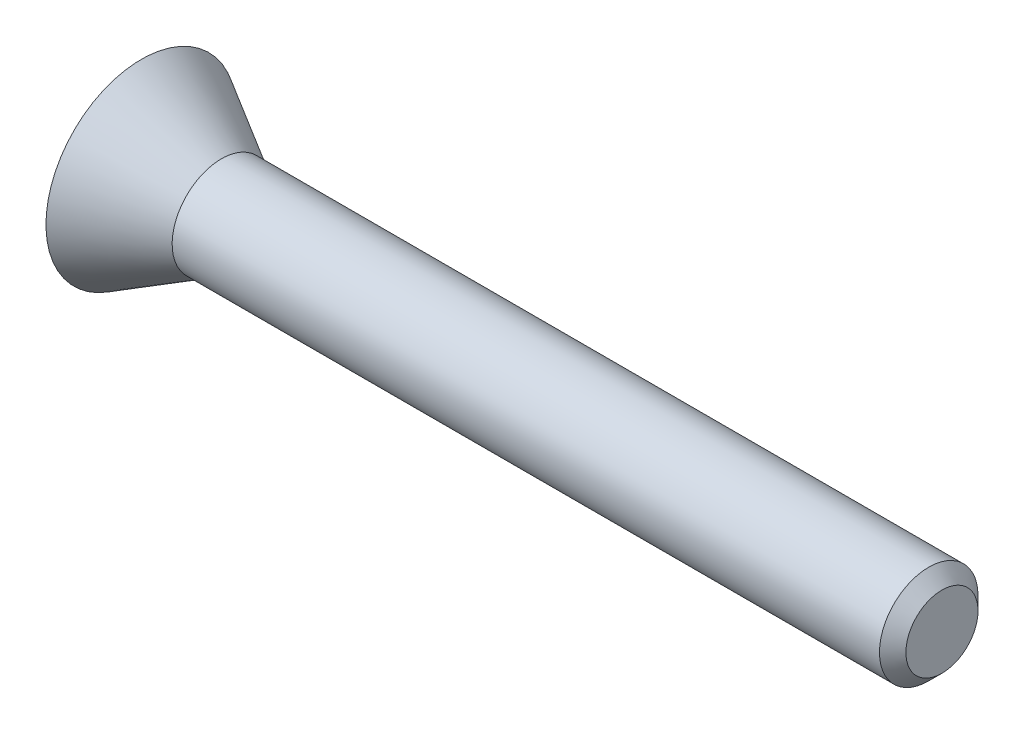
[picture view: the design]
ISO-10303-21;
HEADER;
FILE_DESCRIPTION(('STEP AP214'),'2;1');
FILE_NAME('part.step','',(''),(''),'','','');
FILE_SCHEMA(('AUTOMOTIVE_DESIGN { 1 0 10303 214 1 1 1 1 }'));
ENDSEC;
DATA;
#1=APPLICATION_CONTEXT('core data for automotive mechanical design processes');
#2=APPLICATION_PROTOCOL_DEFINITION('international standard','automotive_design',2000,#1);
#3=PRODUCT_CONTEXT('',#1,'mechanical');
#4=PRODUCT('Part','Part','',(#3));
#5=PRODUCT_RELATED_PRODUCT_CATEGORY('part','',(#4));
#6=PRODUCT_DEFINITION_FORMATION('','',#4);
#7=PRODUCT_DEFINITION_CONTEXT('part definition',#1,'design');
#8=PRODUCT_DEFINITION('design','',#6,#7);
#9=PRODUCT_DEFINITION_SHAPE('','',#8);
#10=(LENGTH_UNIT() NAMED_UNIT(*) SI_UNIT(.MILLI.,.METRE.));
#11=(NAMED_UNIT(*) PLANE_ANGLE_UNIT() SI_UNIT($,.RADIAN.));
#12=(NAMED_UNIT(*) SI_UNIT($,.STERADIAN.) SOLID_ANGLE_UNIT());
#13=UNCERTAINTY_MEASURE_WITH_UNIT(LENGTH_MEASURE(1.E-05),#10,'distance_accuracy_value','');
#14=(GEOMETRIC_REPRESENTATION_CONTEXT(3) GLOBAL_UNCERTAINTY_ASSIGNED_CONTEXT((#13)) GLOBAL_UNIT_ASSIGNED_CONTEXT((#10,
#11,#12)) REPRESENTATION_CONTEXT('',''));
#15=CARTESIAN_POINT('',(0.,0.,0.));
#16=DIRECTION('',(0.,0.,1.));
#17=DIRECTION('',(1.,0.,0.));
#18=AXIS2_PLACEMENT_3D('',#15,#16,#17);
#19=CARTESIAN_POINT('',(-6.5,0.,0.));
#20=DIRECTION('',(1.,0.,0.));
#21=DIRECTION('',(0.,0.,-1.));
#22=AXIS2_PLACEMENT_3D('',#19,#20,#21);
#23=PLANE('',#22);
#24=DIRECTION('',(0.,-1.,0.));
#25=VECTOR('',#24,1.);
#26=CARTESIAN_POINT('',(-6.5,0.45,-0.99468363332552));
#27=LINE('',#26,#25);
#28=CARTESIAN_POINT('',(-6.5,0.45,-0.99468363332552));
#29=VERTEX_POINT('',#28);
#30=CARTESIAN_POINT('',(-6.5,0.299512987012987,-0.99468363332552));
#31=VERTEX_POINT('',#30);
#32=EDGE_CURVE('E298',#29,#31,#27,.T.);
#33=ORIENTED_EDGE('',*,*,#32,.F.);
#34=DIRECTION('',(0.,0.,-1.));
#35=VECTOR('',#34,1.);
#36=CARTESIAN_POINT('',(-6.5,0.45,-0.311891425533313));
#37=LINE('',#36,#35);
#38=CARTESIAN_POINT('',(-6.5,0.45,-0.311891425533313));
#39=VERTEX_POINT('',#38);
#40=EDGE_CURVE('E54',#39,#29,#37,.T.);
#41=ORIENTED_EDGE('',*,*,#40,.F.);
#42=DIRECTION('',(0.,1.,0.));
#43=VECTOR('',#42,1.);
#44=CARTESIAN_POINT('',(-6.5,0.0448051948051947,-0.311891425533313));
#45=LINE('',#44,#43);
#46=CARTESIAN_POINT('',(-6.5,0.0448051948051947,-0.311891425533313));
#47=VERTEX_POINT('',#46);
#48=EDGE_CURVE('E275',#47,#39,#45,.T.);
#49=ORIENTED_EDGE('',*,*,#48,.F.);
#50=DIRECTION('',(0.,0.,1.));
#51=VECTOR('',#50,1.);
#52=CARTESIAN_POINT('',(-6.5,0.0448051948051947,-0.537134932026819));
#53=LINE('',#52,#51);
#54=CARTESIAN_POINT('',(-6.5,0.0448051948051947,-0.537134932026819));
#55=VERTEX_POINT('',#54);
#56=EDGE_CURVE('E278',#55,#47,#53,.T.);
#57=ORIENTED_EDGE('',*,*,#56,.F.);
#58=DIRECTION('',(0.,-1.,0.));
#59=VECTOR('',#58,1.);
#60=CARTESIAN_POINT('',(-6.5,0.231818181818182,-0.537134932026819));
#61=LINE('',#60,#59);
#62=CARTESIAN_POINT('',(-6.5,0.231818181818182,-0.537134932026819));
#63=VERTEX_POINT('',#62);
#64=EDGE_CURVE('E312',#63,#55,#61,.T.);
#65=ORIENTED_EDGE('',*,*,#64,.F.);
#66=DIRECTION('',(0.,0.,1.));
#67=VECTOR('',#66,1.);
#68=CARTESIAN_POINT('',(-6.5,0.231818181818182,-0.742410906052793));
#69=LINE('',#68,#67);
#70=CARTESIAN_POINT('',(-6.5,0.231818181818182,-0.742410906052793));
#71=VERTEX_POINT('',#70);
#72=EDGE_CURVE('E309',#71,#63,#69,.T.);
#73=ORIENTED_EDGE('',*,*,#72,.F.);
#74=DIRECTION('',(0.,0.966781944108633,-0.255602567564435));
#75=VECTOR('',#74,1.);
#76=CARTESIAN_POINT('',(-6.5,-0.75,-0.482832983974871));
#77=LINE('',#76,#75);
#78=CARTESIAN_POINT('',(-6.5,-0.75,-0.482832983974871));
#79=VERTEX_POINT('',#78);
#80=EDGE_CURVE('E306',#79,#71,#77,.T.);
#81=ORIENTED_EDGE('',*,*,#80,.F.);
#82=DIRECTION('',(0.,0.,1.));
#83=VECTOR('',#82,1.);
#84=CARTESIAN_POINT('',(-6.5,-0.75,-0.726826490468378));
#85=LINE('',#84,#83);
#86=CARTESIAN_POINT('',(-6.5,-0.75,-0.726826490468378));
#87=VERTEX_POINT('',#86);
#88=EDGE_CURVE('E303',#87,#79,#85,.T.);
#89=ORIENTED_EDGE('',*,*,#88,.F.);
#90=DIRECTION('',(0.,-0.968940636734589,0.247293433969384));
#91=VECTOR('',#90,1.);
#92=CARTESIAN_POINT('',(-6.5,0.299512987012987,-0.99468363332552));
#93=LINE('',#92,#91);
#94=EDGE_CURVE('E300',#31,#87,#93,.T.);
#95=ORIENTED_EDGE('',*,*,#94,.F.);
#96=EDGE_LOOP('',(#33,#41,#49,#57,#65,#73,#81,#89,#95));
#97=FACE_BOUND('',#96,.T.);
#98=DIRECTION('',(0.,1.,0.));
#99=VECTOR('',#98,1.);
#100=CARTESIAN_POINT('',(-6.5,-0.75,1.02208584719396));
#101=LINE('',#100,#99);
#102=CARTESIAN_POINT('',(-6.5,-0.75,1.02208584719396));
#103=VERTEX_POINT('',#102);
#104=CARTESIAN_POINT('',(-6.5,-0.545941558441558,1.02208584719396));
#105=VERTEX_POINT('',#104);
#106=EDGE_CURVE('E427',#103,#105,#101,.T.);
#107=ORIENTED_EDGE('',*,*,#106,.F.);
#108=DIRECTION('',(0.,0.,1.));
#109=VECTOR('',#108,1.);
#110=CARTESIAN_POINT('',(-6.5,-0.75,0.315430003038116));
#111=LINE('',#110,#109);
#112=CARTESIAN_POINT('',(-6.5,-0.75,0.315430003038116));
#113=VERTEX_POINT('',#112);
#114=EDGE_CURVE('E62',#113,#103,#111,.T.);
#115=ORIENTED_EDGE('',*,*,#114,.F.);
#116=DIRECTION('',(0.,-1.,0.));
#117=VECTOR('',#116,1.);
#118=CARTESIAN_POINT('',(-6.5,-0.531818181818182,0.315430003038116));
#119=LINE('',#118,#117);
#120=CARTESIAN_POINT('',(-6.5,-0.531818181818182,0.315430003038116));
#121=VERTEX_POINT('',#120);
#122=EDGE_CURVE('E336',#121,#113,#119,.T.);
#123=ORIENTED_EDGE('',*,*,#122,.F.);
#124=DIRECTION('',(0.,0.,-1.));
#125=VECTOR('',#124,1.);
#126=CARTESIAN_POINT('',(-6.5,-0.531818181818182,0.723790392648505));
#127=LINE('',#126,#125);
#128=CARTESIAN_POINT('',(-6.5,-0.531818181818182,0.723790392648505));
#129=VERTEX_POINT('',#128);
#130=EDGE_CURVE('E535',#129,#121,#127,.T.);
#131=ORIENTED_EDGE('',*,*,#130,.F.);
#132=DIRECTION('',(0.,-0.786034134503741,0.618183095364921));
#133=VECTOR('',#132,1.);
#134=CARTESIAN_POINT('',(-6.5,-0.157792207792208,0.429634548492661));
#135=LINE('',#134,#133);
#136=CARTESIAN_POINT('',(-6.5,-0.157792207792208,0.429634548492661));
#137=VERTEX_POINT('',#136);
#138=EDGE_CURVE('E538',#137,#129,#135,.T.);
#139=ORIENTED_EDGE('',*,*,#138,.F.);
#140=CARTESIAN_POINT('',(-6.5,0.150974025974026,0.322004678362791));
#141=CARTESIAN_POINT('',(-6.5,0.137320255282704,0.322315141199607));
#142=CARTESIAN_POINT('',(-6.5,0.10998858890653,0.322936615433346));
#143=CARTESIAN_POINT('',(-6.5,0.069082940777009,0.328546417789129));
#144=CARTESIAN_POINT('',(-6.5,0.0283861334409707,0.337586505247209));
#145=CARTESIAN_POINT('',(-6.5,-0.0119052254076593,0.350001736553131));
#146=CARTESIAN_POINT('',(-6.5,-0.0510932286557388,0.365424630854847));
#147=CARTESIAN_POINT('',(-6.5,-0.0886411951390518,0.383935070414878));
#148=CARTESIAN_POINT('',(-6.5,-0.124565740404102,0.404826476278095));
#149=CARTESIAN_POINT('',(-6.5,-0.146737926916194,0.421381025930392));
#150=CARTESIAN_POINT('',(-6.5,-0.157792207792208,0.429634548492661));
#151=B_SPLINE_CURVE_WITH_KNOTS('',3,(#140,#141,#142,#143,#144,#145,#146,#147,#148,#149,#150),
.UNSPECIFIED.,.F.,.F.,(4,1,1,1,1,1,1,1,4),(0.,0.123046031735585,0.246309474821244,
0.371480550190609,0.498560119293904,0.626024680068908,0.750715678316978,0.875715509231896,1.),.UNSPECIFIED.);
#152=CARTESIAN_POINT('',(-6.5,0.150974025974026,0.322004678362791));
#153=VERTEX_POINT('',#152);
#154=EDGE_CURVE('E541',#153,#137,#151,.T.);
#155=ORIENTED_EDGE('',*,*,#154,.F.);
#156=DIRECTION('',(0.,-1.,0.));
#157=VECTOR('',#156,1.);
#158=CARTESIAN_POINT('',(-6.5,0.151948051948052,0.322004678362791));
#159=LINE('',#158,#157);
#160=CARTESIAN_POINT('',(-6.5,0.151948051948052,0.322004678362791));
#161=VERTEX_POINT('',#160);
#162=EDGE_CURVE('E546',#161,#153,#159,.T.);
#163=ORIENTED_EDGE('',*,*,#162,.F.);
#164=CARTESIAN_POINT('',(-6.5,0.465584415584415,0.675332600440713));
#165=CARTESIAN_POINT('',(-6.5,0.465390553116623,0.661685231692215));
#166=CARTESIAN_POINT('',(-6.5,0.465013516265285,0.635142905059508));
#167=CARTESIAN_POINT('',(-6.5,0.460943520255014,0.596501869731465));
#168=CARTESIAN_POINT('',(-6.5,0.454800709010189,0.560144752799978));
#169=CARTESIAN_POINT('',(-6.5,0.445814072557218,0.526130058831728));
#170=CARTESIAN_POINT('',(-6.5,0.434091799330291,0.494594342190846));
#171=CARTESIAN_POINT('',(-6.5,0.419957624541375,0.465443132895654));
#172=CARTESIAN_POINT('',(-6.5,0.403291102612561,0.43861549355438));
#173=CARTESIAN_POINT('',(-6.5,0.38405660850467,0.414316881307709));
#174=CARTESIAN_POINT('',(-6.5,0.362603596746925,0.392454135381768));
#175=CARTESIAN_POINT('',(-6.5,0.338714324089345,0.373636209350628));
#176=CARTESIAN_POINT('',(-6.5,0.312871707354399,0.35734617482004));
#177=CARTESIAN_POINT('',(-6.5,0.2845745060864,0.344612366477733));
#178=CARTESIAN_POINT('',(-6.5,0.254488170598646,0.334128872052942));
#179=CARTESIAN_POINT('',(-6.5,0.222073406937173,0.327340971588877));
#180=CARTESIAN_POINT('',(-6.5,0.187711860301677,0.322766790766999));
#181=CARTESIAN_POINT('',(-6.5,0.164058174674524,0.322262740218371));
#182=CARTESIAN_POINT('',(-6.5,0.151948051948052,0.322004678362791));
#183=B_SPLINE_CURVE_WITH_KNOTS('',3,(#164,#165,#166,#167,#168,#169,#170,#171,#172,#173,#174,
#175,#176,#177,#178,#179,#180,#181,#182),.UNSPECIFIED.,.F.,.F.,(4,1,1,1,1,1,1,1,1,1,1,1,1,1,1,1,
4),(0.,0.0762312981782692,0.148259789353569,0.216860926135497,0.28210063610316,
0.344528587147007,0.404571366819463,0.462840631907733,0.520642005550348,0.577409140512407,
0.633580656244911,0.690215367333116,0.747647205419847,0.806597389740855,0.867894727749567,
0.932365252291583,1.),.UNSPECIFIED.);
#184=CARTESIAN_POINT('',(-6.5,0.465584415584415,0.675332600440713));
#185=VERTEX_POINT('',#184);
#186=EDGE_CURVE('E552',#185,#161,#183,.T.);
#187=ORIENTED_EDGE('',*,*,#186,.F.);
#188=CARTESIAN_POINT('',(-6.5,0.105438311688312,1.03693974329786));
#189=CARTESIAN_POINT('',(-6.5,0.11934799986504,1.03580067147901));
#190=CARTESIAN_POINT('',(-6.5,0.146499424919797,1.03357722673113));
#191=CARTESIAN_POINT('',(-6.5,0.185775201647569,1.02628780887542));
#192=CARTESIAN_POINT('',(-6.5,0.22277029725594,1.0168665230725));
#193=CARTESIAN_POINT('',(-6.5,0.257477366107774,1.00488137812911));
#194=CARTESIAN_POINT('',(-6.5,0.289494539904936,0.989480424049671));
#195=CARTESIAN_POINT('',(-6.5,0.3194911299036,0.972176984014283));
#196=CARTESIAN_POINT('',(-6.5,0.346539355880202,0.95136528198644));
#197=CARTESIAN_POINT('',(-6.5,0.371544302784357,0.928583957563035));
#198=CARTESIAN_POINT('',(-6.5,0.393568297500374,0.903209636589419));
#199=CARTESIAN_POINT('',(-6.5,0.412996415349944,0.876153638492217));
#200=CARTESIAN_POINT('',(-6.5,0.429163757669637,0.847006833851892));
#201=CARTESIAN_POINT('',(-6.5,0.442575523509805,0.81621233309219));
#202=CARTESIAN_POINT('',(-6.5,0.452754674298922,0.78342871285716));
#203=CARTESIAN_POINT('',(-6.5,0.460379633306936,0.749084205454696));
#204=CARTESIAN_POINT('',(-6.5,0.464776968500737,0.71278460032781));
#205=CARTESIAN_POINT('',(-6.5,0.465311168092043,0.688006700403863));
#206=CARTESIAN_POINT('',(-6.5,0.465584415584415,0.675332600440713));
#207=B_SPLINE_CURVE_WITH_KNOTS('',3,(#188,#189,#190,#191,#192,#193,#194,#195,#196,#197,#198,
#199,#200,#201,#202,#203,#204,#205,#206),.UNSPECIFIED.,.F.,.F.,(4,1,1,1,1,1,1,1,1,1,1,1,1,1,1,1,
4),(0.,0.0733268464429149,0.14313249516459,0.209679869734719,0.273918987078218,0.33576228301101,
0.396210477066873,0.45560885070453,0.514796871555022,0.573764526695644,0.631900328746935,
0.689592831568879,0.748648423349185,0.808163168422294,0.86976604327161,0.933384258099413,1.),.UNSPECIFIED.);
#208=CARTESIAN_POINT('',(-6.5,0.105438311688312,1.03693974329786));
#209=VERTEX_POINT('',#208);
#210=EDGE_CURVE('E557',#209,#185,#207,.T.);
#211=ORIENTED_EDGE('',*,*,#210,.F.);
#212=DIRECTION('',(0.,1.,0.));
#213=VECTOR('',#212,1.);
#214=CARTESIAN_POINT('',(-6.5,0.104707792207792,1.03693974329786));
#215=LINE('',#214,#213);
#216=CARTESIAN_POINT('',(-6.5,0.104707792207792,1.03693974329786));
#217=VERTEX_POINT('',#216);
#218=EDGE_CURVE('E565',#217,#209,#215,.T.);
#219=ORIENTED_EDGE('',*,*,#218,.F.);
#220=DIRECTION('',(0.,0.,1.));
#221=VECTOR('',#220,1.);
#222=CARTESIAN_POINT('',(-6.5,0.104707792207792,0.8060955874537));
#223=LINE('',#222,#221);
#224=CARTESIAN_POINT('',(-6.5,0.104707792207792,0.8060955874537));
#225=VERTEX_POINT('',#224);
#226=EDGE_CURVE('E571',#225,#217,#223,.T.);
#227=ORIENTED_EDGE('',*,*,#226,.F.);
#228=DIRECTION('',(0.,-1.,0.));
#229=VECTOR('',#228,1.);
#230=CARTESIAN_POINT('',(-6.5,0.105438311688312,0.8060955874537));
#231=LINE('',#230,#229);
#232=CARTESIAN_POINT('',(-6.5,0.105438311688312,0.8060955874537));
#233=VERTEX_POINT('',#232);
#234=EDGE_CURVE('E574',#233,#225,#231,.T.);
#235=ORIENTED_EDGE('',*,*,#234,.F.);
#236=CARTESIAN_POINT('',(-6.5,0.247402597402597,0.673628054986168));
#237=CARTESIAN_POINT('',(-6.5,0.247058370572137,0.682449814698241));
#238=CARTESIAN_POINT('',(-6.5,0.246389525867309,0.699590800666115));
#239=CARTESIAN_POINT('',(-6.5,0.238976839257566,0.723856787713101));
#240=CARTESIAN_POINT('',(-6.5,0.227349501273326,0.745722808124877));
#241=CARTESIAN_POINT('',(-6.5,0.210758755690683,0.764573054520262));
#242=CARTESIAN_POINT('',(-6.5,0.189928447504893,0.78018248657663));
#243=CARTESIAN_POINT('',(-6.5,0.165399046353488,0.792851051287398));
#244=CARTESIAN_POINT('',(-6.5,0.136727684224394,0.801455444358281));
#245=CARTESIAN_POINT('',(-6.5,0.116203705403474,0.804499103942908));
#246=CARTESIAN_POINT('',(-6.5,0.105438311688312,0.8060955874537));
#247=B_SPLINE_CURVE_WITH_KNOTS('',3,(#236,#237,#238,#239,#240,#241,#242,#243,#244,#245,#246),
.UNSPECIFIED.,.F.,.F.,(4,1,1,1,1,1,1,1,4),(0.,0.122603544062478,0.238222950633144,
0.350089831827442,0.465559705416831,0.58502806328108,0.711014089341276,0.848418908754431,1.),.UNSPECIFIED.);
#248=CARTESIAN_POINT('',(-6.5,0.247402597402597,0.673628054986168));
#249=VERTEX_POINT('',#248);
#250=EDGE_CURVE('E577',#249,#233,#247,.T.);
#251=ORIENTED_EDGE('',*,*,#250,.F.);
#252=CARTESIAN_POINT('',(-6.5,0.145616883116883,0.553822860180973));
#253=CARTESIAN_POINT('',(-6.5,0.153289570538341,0.554155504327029));
#254=CARTESIAN_POINT('',(-6.5,0.16798921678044,0.55479279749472));
#255=CARTESIAN_POINT('',(-6.5,0.188701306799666,0.560797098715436));
#256=CARTESIAN_POINT('',(-6.5,0.206738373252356,0.570637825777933));
#257=CARTESIAN_POINT('',(-6.5,0.221636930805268,0.584732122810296));
#258=CARTESIAN_POINT('',(-6.5,0.233420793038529,0.602278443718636));
#259=CARTESIAN_POINT('',(-6.5,0.241725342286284,0.623273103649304));
#260=CARTESIAN_POINT('',(-6.5,0.246487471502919,0.647441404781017));
#261=CARTESIAN_POINT('',(-6.5,0.247086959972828,0.664595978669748));
#262=CARTESIAN_POINT('',(-6.5,0.247402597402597,0.673628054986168));
#263=B_SPLINE_CURVE_WITH_KNOTS('',3,(#252,#253,#254,#255,#256,#257,#258,#259,#260,#261,#262),
.UNSPECIFIED.,.F.,.F.,(4,1,1,1,1,1,1,1,4),(0.,0.128749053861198,0.246662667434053,
0.359069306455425,0.47107757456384,0.588039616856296,0.711712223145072,0.848213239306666,1.),.UNSPECIFIED.);
#264=CARTESIAN_POINT('',(-6.5,0.145616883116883,0.553822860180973));
#265=VERTEX_POINT('',#264);
#266=EDGE_CURVE('E582',#265,#249,#263,.T.);
#267=ORIENTED_EDGE('',*,*,#266,.F.);
#268=DIRECTION('',(0.,1.,0.));
#269=VECTOR('',#268,1.);
#270=CARTESIAN_POINT('',(-6.5,0.143912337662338,0.553822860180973));
#271=LINE('',#270,#269);
#272=CARTESIAN_POINT('',(-6.5,0.143912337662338,0.553822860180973));
#273=VERTEX_POINT('',#272);
#274=EDGE_CURVE('E590',#273,#265,#271,.T.);
#275=ORIENTED_EDGE('',*,*,#274,.F.);
#276=CARTESIAN_POINT('',(-6.5,-0.00267857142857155,0.612020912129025));
#277=CARTESIAN_POINT('',(-6.5,0.00942362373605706,0.603432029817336));
#278=CARTESIAN_POINT('',(-6.5,0.0330043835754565,0.586696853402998));
#279=CARTESIAN_POINT('',(-6.5,0.0653877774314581,0.571550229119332));
#280=CARTESIAN_POINT('',(-6.5,0.0907767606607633,0.562114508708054));
#281=CARTESIAN_POINT('',(-6.5,0.109188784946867,0.557617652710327));
#282=CARTESIAN_POINT('',(-6.5,0.126755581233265,0.554409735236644));
#283=CARTESIAN_POINT('',(-6.5,0.138298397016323,0.55401489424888));
#284=CARTESIAN_POINT('',(-6.5,0.143912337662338,0.553822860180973));
#285=B_SPLINE_CURVE_WITH_KNOTS('',3,(#276,#277,#278,#279,#280,#281,#282,#283,#284),
.UNSPECIFIED.,.F.,.F.,(4,1,1,1,1,1,4),(0.,0.27737542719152,0.540457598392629,0.666416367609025,
0.784009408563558,0.894951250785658,1.),.UNSPECIFIED.);
#286=CARTESIAN_POINT('',(-6.5,-0.00267857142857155,0.612020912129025));
#287=VERTEX_POINT('',#286);
#288=EDGE_CURVE('E596',#287,#273,#285,.T.);
#289=ORIENTED_EDGE('',*,*,#288,.F.);
#290=DIRECTION('',(0.,0.798150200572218,-0.602458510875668));
#291=VECTOR('',#290,1.);
#292=CARTESIAN_POINT('',(-6.5,-0.545941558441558,1.02208584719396));
#293=LINE('',#292,#291);
#294=EDGE_CURVE('E601',#105,#287,#293,.T.);
#295=ORIENTED_EDGE('',*,*,#294,.F.);
#296=EDGE_LOOP('',(#107,#115,#123,#131,#139,#155,#163,#187,#211,#219,#227,#235,#251,#267,#275,
#289,#295));
#297=FACE_BOUND('',#296,.T.);
#298=DIRECTION('',(0.,1.,0.));
#299=VECTOR('',#298,1.);
#300=CARTESIAN_POINT('',(-6.5,0.68,0.155));
#301=LINE('',#300,#299);
#302=CARTESIAN_POINT('',(-6.5,-1.025,0.155));
#303=VERTEX_POINT('',#302);
#304=CARTESIAN_POINT('',(-6.5,0.68,0.155));
#305=VERTEX_POINT('',#304);
#306=EDGE_CURVE('E433',#303,#305,#301,.T.);
#307=ORIENTED_EDGE('',*,*,#306,.F.);
#308=CARTESIAN_POINT('',(-6.5,-1.025,0.));
#309=DIRECTION('',(-1.,0.,0.));
#310=DIRECTION('',(0.,0.,1.));
#311=AXIS2_PLACEMENT_3D('',#308,#309,#310);
#312=CIRCLE('',#311,0.155);
#313=CARTESIAN_POINT('',(-6.5,-1.025,-0.155));
#314=VERTEX_POINT('',#313);
#315=EDGE_CURVE('E477',#314,#303,#312,.T.);
#316=ORIENTED_EDGE('',*,*,#315,.F.);
#317=DIRECTION('',(0.,-1.,0.));
#318=VECTOR('',#317,1.);
#319=CARTESIAN_POINT('',(-6.5,0.68,-0.155));
#320=LINE('',#319,#318);
#321=CARTESIAN_POINT('',(-6.5,0.68,-0.155));
#322=VERTEX_POINT('',#321);
#323=EDGE_CURVE('E460',#322,#314,#320,.T.);
#324=ORIENTED_EDGE('',*,*,#323,.F.);
#325=DIRECTION('',(0.,0.,1.));
#326=VECTOR('',#325,1.);
#327=CARTESIAN_POINT('',(-6.5,0.68,-0.37));
#328=LINE('',#327,#326);
#329=CARTESIAN_POINT('',(-6.5,0.68,-0.37));
#330=VERTEX_POINT('',#329);
#331=EDGE_CURVE('E464',#330,#322,#328,.T.);
#332=ORIENTED_EDGE('',*,*,#331,.F.);
#333=DIRECTION('',(0.,-0.858712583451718,-0.512457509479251));
#334=VECTOR('',#333,1.);
#335=CARTESIAN_POINT('',(-6.5,1.3,0.));
#336=LINE('',#335,#334);
#337=CARTESIAN_POINT('',(-6.5,1.3,0.));
#338=VERTEX_POINT('',#337);
#339=EDGE_CURVE('E467',#338,#330,#336,.T.);
#340=ORIENTED_EDGE('',*,*,#339,.F.);
#341=DIRECTION('',(0.,0.858712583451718,-0.512457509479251));
#342=VECTOR('',#341,1.);
#343=CARTESIAN_POINT('',(-6.5,1.3,0.));
#344=LINE('',#343,#342);
#345=CARTESIAN_POINT('',(-6.5,0.68,0.37));
#346=VERTEX_POINT('',#345);
#347=EDGE_CURVE('E470',#346,#338,#344,.T.);
#348=ORIENTED_EDGE('',*,*,#347,.F.);
#349=DIRECTION('',(0.,0.,1.));
#350=VECTOR('',#349,1.);
#351=CARTESIAN_POINT('',(-6.5,0.68,0.37));
#352=LINE('',#351,#350);
#353=EDGE_CURVE('E473',#305,#346,#352,.T.);
#354=ORIENTED_EDGE('',*,*,#353,.F.);
#355=EDGE_LOOP('',(#307,#316,#324,#332,#340,#348,#354));
#356=FACE_BOUND('',#355,.T.);
#357=CARTESIAN_POINT('',(-6.5,0.,0.));
#358=DIRECTION('',(-1.,0.,0.));
#359=DIRECTION('',(0.,-1.,0.));
#360=AXIS2_PLACEMENT_3D('',#357,#358,#359);
#361=CIRCLE('',#360,1.55);
#362=CARTESIAN_POINT('',(-6.5,-1.55000000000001,0.));
#363=VERTEX_POINT('',#362);
#364=EDGE_CURVE('E436',#363,#363,#361,.T.);
#365=ORIENTED_EDGE('',*,*,#364,.T.);
#366=EDGE_LOOP('',(#365));
#367=FACE_BOUND('',#366,.T.);
#368=ADVANCED_FACE('F39',(#97,#297,#356,#367),#23,.F.);
#369=CARTESIAN_POINT('',(-6.5,0.,0.));
#370=DIRECTION('',(-1.,0.,0.));
#371=DIRECTION('',(0.,-1.,0.));
#372=AXIS2_PLACEMENT_3D('',#369,#370,#371);
#373=CONICAL_SURFACE('',#372,1.55,0.523598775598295);
#374=CARTESIAN_POINT('',(-5.20096189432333,0.,0.));
#375=DIRECTION('',(-1.,0.,0.));
#376=DIRECTION('',(0.,-1.,0.));
#377=AXIS2_PLACEMENT_3D('',#374,#375,#376);
#378=CIRCLE('',#377,0.800000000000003);
#379=CARTESIAN_POINT('',(-5.20096189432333,-0.800000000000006,0.));
#380=VERTEX_POINT('',#379);
#381=EDGE_CURVE('E438',#380,#380,#378,.T.);
#382=ORIENTED_EDGE('',*,*,#381,.T.);
#383=EDGE_LOOP('',(#382));
#384=FACE_BOUND('',#383,.T.);
#385=ORIENTED_EDGE('',*,*,#364,.F.);
#386=EDGE_LOOP('',(#385));
#387=FACE_BOUND('',#386,.T.);
#388=ADVANCED_FACE('F410',(#384,#387),#373,.T.);
#389=CARTESIAN_POINT('',(-6.5,0.,0.));
#390=DIRECTION('',(-1.,0.,0.));
#391=DIRECTION('',(0.,-1.,0.));
#392=AXIS2_PLACEMENT_3D('',#389,#390,#391);
#393=CYLINDRICAL_SURFACE('',#392,0.800000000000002);
#394=CARTESIAN_POINT('',(6.2855,0.,0.));
#395=DIRECTION('',(1.,0.,0.));
#396=DIRECTION('',(0.,1.,0.));
#397=AXIS2_PLACEMENT_3D('',#394,#395,#396);
#398=CIRCLE('',#397,0.800000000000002);
#399=CARTESIAN_POINT('',(6.2855,0.800000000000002,0.));
#400=VERTEX_POINT('',#399);
#401=EDGE_CURVE('E47',#400,#400,#398,.F.);
#402=ORIENTED_EDGE('',*,*,#401,.T.);
#403=EDGE_LOOP('',(#402));
#404=FACE_BOUND('',#403,.T.);
#405=ORIENTED_EDGE('',*,*,#381,.F.);
#406=EDGE_LOOP('',(#405));
#407=FACE_BOUND('',#406,.T.);
#408=ADVANCED_FACE('F407',(#404,#407),#393,.T.);
#409=CARTESIAN_POINT('',(6.5,0.,0.));
#410=DIRECTION('',(1.,0.,0.));
#411=DIRECTION('',(0.,0.,-1.));
#412=AXIS2_PLACEMENT_3D('',#409,#410,#411);
#413=PLANE('',#412);
#414=CARTESIAN_POINT('',(6.5,0.,0.));
#415=DIRECTION('',(1.,0.,0.));
#416=DIRECTION('',(0.,0.,-1.));
#417=AXIS2_PLACEMENT_3D('',#414,#415,#416);
#418=CIRCLE('',#417,0.585500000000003);
#419=CARTESIAN_POINT('',(6.5,0.,-0.585500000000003));
#420=VERTEX_POINT('',#419);
#421=EDGE_CURVE('E11',#420,#420,#418,.T.);
#422=ORIENTED_EDGE('',*,*,#421,.T.);
#423=EDGE_LOOP('',(#422));
#424=FACE_BOUND('',#423,.T.);
#425=ADVANCED_FACE('F405',(#424),#413,.T.);
#426=CARTESIAN_POINT('',(-6.1,-1.025,0.));
#427=DIRECTION('',(-1.,0.,0.));
#428=DIRECTION('',(0.,0.,1.));
#429=AXIS2_PLACEMENT_3D('',#426,#427,#428);
#430=CYLINDRICAL_SURFACE('',#429,0.155);
#431=ORIENTED_EDGE('',*,*,#315,.T.);
#432=DIRECTION('',(-1.,0.,0.));
#433=VECTOR('',#432,1.);
#434=CARTESIAN_POINT('',(-6.1,-1.025,0.155));
#435=LINE('',#434,#433);
#436=CARTESIAN_POINT('',(-6.1,-1.025,0.155));
#437=VERTEX_POINT('',#436);
#438=EDGE_CURVE('E445',#437,#303,#435,.T.);
#439=ORIENTED_EDGE('',*,*,#438,.F.);
#440=CARTESIAN_POINT('',(-6.1,-1.025,0.));
#441=DIRECTION('',(-1.,0.,0.));
#442=DIRECTION('',(0.,0.,1.));
#443=AXIS2_PLACEMENT_3D('',#440,#441,#442);
#444=CIRCLE('',#443,0.155);
#445=CARTESIAN_POINT('',(-6.1,-1.025,-0.155));
#446=VERTEX_POINT('',#445);
#447=EDGE_CURVE('E463',#446,#437,#444,.T.);
#448=ORIENTED_EDGE('',*,*,#447,.F.);
#449=DIRECTION('',(-1.,0.,0.));
#450=VECTOR('',#449,1.);
#451=CARTESIAN_POINT('',(-6.1,-1.025,-0.155));
#452=LINE('',#451,#450);
#453=EDGE_CURVE('E442',#446,#314,#452,.T.);
#454=ORIENTED_EDGE('',*,*,#453,.T.);
#455=EDGE_LOOP('',(#431,#439,#448,#454));
#456=FACE_BOUND('',#455,.T.);
#457=ADVANCED_FACE('F383',(#456),#430,.F.);
#458=CARTESIAN_POINT('',(-6.1,0.68,-0.155));
#459=DIRECTION('',(0.,0.,-1.));
#460=DIRECTION('',(0.,1.,0.));
#461=AXIS2_PLACEMENT_3D('',#458,#459,#460);
#462=PLANE('',#461);
#463=ORIENTED_EDGE('',*,*,#323,.T.);
#464=ORIENTED_EDGE('',*,*,#453,.F.);
#465=DIRECTION('',(0.,-1.,0.));
#466=VECTOR('',#465,1.);
#467=CARTESIAN_POINT('',(-6.1,0.68,-0.155));
#468=LINE('',#467,#466);
#469=CARTESIAN_POINT('',(-6.1,0.68,-0.155));
#470=VERTEX_POINT('',#469);
#471=EDGE_CURVE('E449',#470,#446,#468,.T.);
#472=ORIENTED_EDGE('',*,*,#471,.F.);
#473=DIRECTION('',(-1.,0.,0.));
#474=VECTOR('',#473,1.);
#475=CARTESIAN_POINT('',(-6.1,0.68,-0.155));
#476=LINE('',#475,#474);
#477=EDGE_CURVE('E457',#470,#322,#476,.T.);
#478=ORIENTED_EDGE('',*,*,#477,.T.);
#479=EDGE_LOOP('',(#463,#464,#472,#478));
#480=FACE_BOUND('',#479,.T.);
#481=ADVANCED_FACE('F379',(#480),#462,.F.);
#482=CARTESIAN_POINT('',(-6.1,0.68,-0.37));
#483=DIRECTION('',(0.,-1.,0.));
#484=DIRECTION('',(0.,0.,-1.));
#485=AXIS2_PLACEMENT_3D('',#482,#483,#484);
#486=PLANE('',#485);
#487=ORIENTED_EDGE('',*,*,#331,.T.);
#488=ORIENTED_EDGE('',*,*,#477,.F.);
#489=DIRECTION('',(0.,0.,1.));
#490=VECTOR('',#489,1.);
#491=CARTESIAN_POINT('',(-6.1,0.68,-0.37));
#492=LINE('',#491,#490);
#493=CARTESIAN_POINT('',(-6.1,0.68,-0.37));
#494=VERTEX_POINT('',#493);
#495=EDGE_CURVE('E482',#494,#470,#492,.T.);
#496=ORIENTED_EDGE('',*,*,#495,.F.);
#497=DIRECTION('',(-1.,0.,0.));
#498=VECTOR('',#497,1.);
#499=CARTESIAN_POINT('',(-6.1,0.68,-0.37));
#500=LINE('',#499,#498);
#501=EDGE_CURVE('E455',#494,#330,#500,.T.);
#502=ORIENTED_EDGE('',*,*,#501,.T.);
#503=EDGE_LOOP('',(#487,#488,#496,#502));
#504=FACE_BOUND('',#503,.T.);
#505=ADVANCED_FACE('F382',(#504),#486,.F.);
#506=CARTESIAN_POINT('',(-6.1,1.3,0.));
#507=DIRECTION('',(0.,0.512457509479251,-0.858712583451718));
#508=DIRECTION('',(0.,0.858712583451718,0.512457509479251));
#509=AXIS2_PLACEMENT_3D('',#506,#507,#508);
#510=PLANE('',#509);
#511=ORIENTED_EDGE('',*,*,#339,.T.);
#512=ORIENTED_EDGE('',*,*,#501,.F.);
#513=DIRECTION('',(0.,-0.858712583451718,-0.512457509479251));
#514=VECTOR('',#513,1.);
#515=CARTESIAN_POINT('',(-6.1,1.3,0.));
#516=LINE('',#515,#514);
#517=CARTESIAN_POINT('',(-6.1,1.3,0.));
#518=VERTEX_POINT('',#517);
#519=EDGE_CURVE('E485',#518,#494,#516,.T.);
#520=ORIENTED_EDGE('',*,*,#519,.F.);
#521=DIRECTION('',(-1.,0.,0.));
#522=VECTOR('',#521,1.);
#523=CARTESIAN_POINT('',(-6.1,1.3,0.));
#524=LINE('',#523,#522);
#525=EDGE_CURVE('E453',#518,#338,#524,.T.);
#526=ORIENTED_EDGE('',*,*,#525,.T.);
#527=EDGE_LOOP('',(#511,#512,#520,#526));
#528=FACE_BOUND('',#527,.T.);
#529=ADVANCED_FACE('F387',(#528),#510,.F.);
#530=CARTESIAN_POINT('',(-6.1,1.3,0.));
#531=DIRECTION('',(0.,0.512457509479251,0.858712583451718));
#532=DIRECTION('',(0.,-0.858712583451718,0.512457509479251));
#533=AXIS2_PLACEMENT_3D('',#530,#531,#532);
#534=PLANE('',#533);
#535=ORIENTED_EDGE('',*,*,#347,.T.);
#536=ORIENTED_EDGE('',*,*,#525,.F.);
#537=DIRECTION('',(0.,0.858712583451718,-0.512457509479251));
#538=VECTOR('',#537,1.);
#539=CARTESIAN_POINT('',(-6.1,1.3,0.));
#540=LINE('',#539,#538);
#541=CARTESIAN_POINT('',(-6.1,0.68,0.37));
#542=VERTEX_POINT('',#541);
#543=EDGE_CURVE('E488',#542,#518,#540,.T.);
#544=ORIENTED_EDGE('',*,*,#543,.F.);
#545=DIRECTION('',(-1.,0.,0.));
#546=VECTOR('',#545,1.);
#547=CARTESIAN_POINT('',(-6.1,0.68,0.37));
#548=LINE('',#547,#546);
#549=EDGE_CURVE('E451',#542,#346,#548,.T.);
#550=ORIENTED_EDGE('',*,*,#549,.T.);
#551=EDGE_LOOP('',(#535,#536,#544,#550));
#552=FACE_BOUND('',#551,.T.);
#553=ADVANCED_FACE('F391',(#552),#534,.F.);
#554=CARTESIAN_POINT('',(-6.1,0.68,0.37));
#555=DIRECTION('',(0.,-1.,0.));
#556=DIRECTION('',(0.,0.,-1.));
#557=AXIS2_PLACEMENT_3D('',#554,#555,#556);
#558=PLANE('',#557);
#559=ORIENTED_EDGE('',*,*,#353,.T.);
#560=ORIENTED_EDGE('',*,*,#549,.F.);
#561=DIRECTION('',(0.,0.,1.));
#562=VECTOR('',#561,1.);
#563=CARTESIAN_POINT('',(-6.1,0.68,0.37));
#564=LINE('',#563,#562);
#565=CARTESIAN_POINT('',(-6.1,0.68,0.155));
#566=VERTEX_POINT('',#565);
#567=EDGE_CURVE('E491',#566,#542,#564,.T.);
#568=ORIENTED_EDGE('',*,*,#567,.F.);
#569=DIRECTION('',(-1.,0.,0.));
#570=VECTOR('',#569,1.);
#571=CARTESIAN_POINT('',(-6.1,0.68,0.155));
#572=LINE('',#571,#570);
#573=EDGE_CURVE('E448',#566,#305,#572,.T.);
#574=ORIENTED_EDGE('',*,*,#573,.T.);
#575=EDGE_LOOP('',(#559,#560,#568,#574));
#576=FACE_BOUND('',#575,.T.);
#577=ADVANCED_FACE('F395',(#576),#558,.F.);
#578=CARTESIAN_POINT('',(-6.1,0.68,0.155));
#579=DIRECTION('',(0.,0.,1.));
#580=DIRECTION('',(0.,-1.,0.));
#581=AXIS2_PLACEMENT_3D('',#578,#579,#580);
#582=PLANE('',#581);
#583=ORIENTED_EDGE('',*,*,#306,.T.);
#584=ORIENTED_EDGE('',*,*,#573,.F.);
#585=DIRECTION('',(0.,1.,0.));
#586=VECTOR('',#585,1.);
#587=CARTESIAN_POINT('',(-6.1,0.68,0.155));
#588=LINE('',#587,#586);
#589=EDGE_CURVE('E494',#437,#566,#588,.T.);
#590=ORIENTED_EDGE('',*,*,#589,.F.);
#591=ORIENTED_EDGE('',*,*,#438,.T.);
#592=EDGE_LOOP('',(#583,#584,#590,#591));
#593=FACE_BOUND('',#592,.T.);
#594=ADVANCED_FACE('F377',(#593),#582,.F.);
#595=CARTESIAN_POINT('',(-6.1,-1.025,0.));
#596=DIRECTION('',(-1.,0.,0.));
#597=DIRECTION('',(0.,0.,1.));
#598=AXIS2_PLACEMENT_3D('',#595,#596,#597);
#599=PLANE('',#598);
#600=ORIENTED_EDGE('',*,*,#447,.T.);
#601=ORIENTED_EDGE('',*,*,#589,.T.);
#602=ORIENTED_EDGE('',*,*,#567,.T.);
#603=ORIENTED_EDGE('',*,*,#543,.T.);
#604=ORIENTED_EDGE('',*,*,#519,.T.);
#605=ORIENTED_EDGE('',*,*,#495,.T.);
#606=ORIENTED_EDGE('',*,*,#471,.T.);
#607=EDGE_LOOP('',(#600,#601,#602,#603,#604,#605,#606));
#608=FACE_BOUND('',#607,.T.);
#609=ADVANCED_FACE('F374',(#608),#599,.T.);
#610=CARTESIAN_POINT('',(6.2855,0.,0.));
#611=DIRECTION('',(-1.,0.,0.));
#612=DIRECTION('',(0.,-1.,0.));
#613=AXIS2_PLACEMENT_3D('',#610,#611,#612);
#614=CONICAL_SURFACE('',#613,0.800000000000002,0.785398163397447);
#615=ORIENTED_EDGE('',*,*,#421,.F.);
#616=EDGE_LOOP('',(#615));
#617=FACE_BOUND('',#616,.T.);
#618=ORIENTED_EDGE('',*,*,#401,.F.);
#619=EDGE_LOOP('',(#618));
#620=FACE_BOUND('',#619,.T.);
#621=ADVANCED_FACE('F41',(#617,#620),#614,.T.);
#622=CARTESIAN_POINT('',(-6.1,-0.75,0.315430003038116));
#623=DIRECTION('',(0.,-1.,0.));
#624=DIRECTION('',(0.,0.,-1.));
#625=AXIS2_PLACEMENT_3D('',#622,#623,#624);
#626=PLANE('',#625);
#627=ORIENTED_EDGE('',*,*,#114,.T.);
#628=DIRECTION('',(-1.,0.,0.));
#629=VECTOR('',#628,1.);
#630=CARTESIAN_POINT('',(-6.1,-0.75,1.02208584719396));
#631=LINE('',#630,#629);
#632=CARTESIAN_POINT('',(-6.1,-0.75,1.02208584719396));
#633=VERTEX_POINT('',#632);
#634=EDGE_CURVE('E499',#633,#103,#631,.T.);
#635=ORIENTED_EDGE('',*,*,#634,.F.);
#636=DIRECTION('',(0.,0.,1.));
#637=VECTOR('',#636,1.);
#638=CARTESIAN_POINT('',(-6.1,-0.75,0.315430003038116));
#639=LINE('',#638,#637);
#640=CARTESIAN_POINT('',(-6.1,-0.75,0.315430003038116));
#641=VERTEX_POINT('',#640);
#642=EDGE_CURVE('E332',#641,#633,#639,.T.);
#643=ORIENTED_EDGE('',*,*,#642,.F.);
#644=DIRECTION('',(-1.,0.,0.));
#645=VECTOR('',#644,1.);
#646=CARTESIAN_POINT('',(-6.1,-0.75,0.315430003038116));
#647=LINE('',#646,#645);
#648=EDGE_CURVE('E479',#641,#113,#647,.T.);
#649=ORIENTED_EDGE('',*,*,#648,.T.);
#650=EDGE_LOOP('',(#627,#635,#643,#649));
#651=FACE_BOUND('',#650,.T.);
#652=ADVANCED_FACE('F370',(#651),#626,.F.);
#653=CARTESIAN_POINT('',(-6.1,-0.531818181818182,0.315430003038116));
#654=DIRECTION('',(0.,0.,-1.));
#655=DIRECTION('',(-1.,0.,0.));
#656=AXIS2_PLACEMENT_3D('',#653,#654,#655);
#657=PLANE('',#656);
#658=ORIENTED_EDGE('',*,*,#122,.T.);
#659=ORIENTED_EDGE('',*,*,#648,.F.);
#660=DIRECTION('',(0.,-1.,0.));
#661=VECTOR('',#660,1.);
#662=CARTESIAN_POINT('',(-6.1,-0.531818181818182,0.315430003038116));
#663=LINE('',#662,#661);
#664=CARTESIAN_POINT('',(-6.1,-0.531818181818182,0.315430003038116));
#665=VERTEX_POINT('',#664);
#666=EDGE_CURVE('E502',#665,#641,#663,.T.);
#667=ORIENTED_EDGE('',*,*,#666,.F.);
#668=DIRECTION('',(-1.,0.,0.));
#669=VECTOR('',#668,1.);
#670=CARTESIAN_POINT('',(-6.1,-0.531818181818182,0.315430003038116));
#671=LINE('',#670,#669);
#672=EDGE_CURVE('E530',#665,#121,#671,.T.);
#673=ORIENTED_EDGE('',*,*,#672,.T.);
#674=EDGE_LOOP('',(#658,#659,#667,#673));
#675=FACE_BOUND('',#674,.T.);
#676=ADVANCED_FACE('F373',(#675),#657,.F.);
#677=CARTESIAN_POINT('',(-6.1,-0.531818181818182,0.723790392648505));
#678=DIRECTION('',(0.,1.,0.));
#679=DIRECTION('',(0.,0.,1.));
#680=AXIS2_PLACEMENT_3D('',#677,#678,#679);
#681=PLANE('',#680);
#682=ORIENTED_EDGE('',*,*,#130,.T.);
#683=ORIENTED_EDGE('',*,*,#672,.F.);
#684=DIRECTION('',(0.,0.,-1.));
#685=VECTOR('',#684,1.);
#686=CARTESIAN_POINT('',(-6.1,-0.531818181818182,0.723790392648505));
#687=LINE('',#686,#685);
#688=CARTESIAN_POINT('',(-6.1,-0.531818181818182,0.723790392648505));
#689=VERTEX_POINT('',#688);
#690=EDGE_CURVE('E611',#689,#665,#687,.T.);
#691=ORIENTED_EDGE('',*,*,#690,.F.);
#692=DIRECTION('',(-1.,0.,0.));
#693=VECTOR('',#692,1.);
#694=CARTESIAN_POINT('',(-6.1,-0.531818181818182,0.723790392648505));
#695=LINE('',#694,#693);
#696=EDGE_CURVE('E528',#689,#129,#695,.T.);
#697=ORIENTED_EDGE('',*,*,#696,.T.);
#698=EDGE_LOOP('',(#682,#683,#691,#697));
#699=FACE_BOUND('',#698,.T.);
#700=ADVANCED_FACE('F724',(#699),#681,.F.);
#701=CARTESIAN_POINT('',(-6.1,-0.157792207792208,0.429634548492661));
#702=DIRECTION('',(0.,-0.618183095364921,-0.786034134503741));
#703=DIRECTION('',(0.,0.786034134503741,-0.618183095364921));
#704=AXIS2_PLACEMENT_3D('',#701,#702,#703);
#705=PLANE('',#704);
#706=ORIENTED_EDGE('',*,*,#138,.T.);
#707=ORIENTED_EDGE('',*,*,#696,.F.);
#708=DIRECTION('',(0.,-0.786034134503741,0.618183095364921));
#709=VECTOR('',#708,1.);
#710=CARTESIAN_POINT('',(-6.1,-0.157792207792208,0.429634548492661));
#711=LINE('',#710,#709);
#712=CARTESIAN_POINT('',(-6.1,-0.157792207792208,0.429634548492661));
#713=VERTEX_POINT('',#712);
#714=EDGE_CURVE('E614',#713,#689,#711,.T.);
#715=ORIENTED_EDGE('',*,*,#714,.F.);
#716=DIRECTION('',(-1.,0.,0.));
#717=VECTOR('',#716,1.);
#718=CARTESIAN_POINT('',(-6.1,-0.157792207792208,0.429634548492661));
#719=LINE('',#718,#717);
#720=EDGE_CURVE('E526',#713,#137,#719,.T.);
#721=ORIENTED_EDGE('',*,*,#720,.T.);
#722=EDGE_LOOP('',(#706,#707,#715,#721));
#723=FACE_BOUND('',#722,.T.);
#724=ADVANCED_FACE('F634',(#723),#705,.F.);
#725=CARTESIAN_POINT('',(-6.1,0.150974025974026,0.322004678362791));
#726=CARTESIAN_POINT('',(-6.1,0.137320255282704,0.322315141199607));
#727=CARTESIAN_POINT('',(-6.1,0.10998858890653,0.322936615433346));
#728=CARTESIAN_POINT('',(-6.1,0.069082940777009,0.328546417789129));
#729=CARTESIAN_POINT('',(-6.1,0.0283861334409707,0.337586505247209));
#730=CARTESIAN_POINT('',(-6.1,-0.0119052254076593,0.350001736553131));
#731=CARTESIAN_POINT('',(-6.1,-0.0510932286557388,0.365424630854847));
#732=CARTESIAN_POINT('',(-6.1,-0.0886411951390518,0.383935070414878));
#733=CARTESIAN_POINT('',(-6.1,-0.124565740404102,0.404826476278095));
#734=CARTESIAN_POINT('',(-6.1,-0.146737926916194,0.421381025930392));
#735=CARTESIAN_POINT('',(-6.1,-0.157792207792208,0.429634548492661));
#736=B_SPLINE_CURVE_WITH_KNOTS('',3,(#725,#726,#727,#728,#729,#730,#731,#732,#733,#734,#735),
.UNSPECIFIED.,.F.,.F.,(4,1,1,1,1,1,1,1,4),(0.,0.123046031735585,0.246309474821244,
0.371480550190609,0.498560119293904,0.626024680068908,0.750715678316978,0.875715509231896,1.),.UNSPECIFIED.);
#737=DIRECTION('',(-1.,0.,0.));
#738=VECTOR('',#737,1.);
#739=SURFACE_OF_LINEAR_EXTRUSION('',#736,#738);
#740=ORIENTED_EDGE('',*,*,#154,.T.);
#741=ORIENTED_EDGE('',*,*,#720,.F.);
#742=CARTESIAN_POINT('',(-6.1,0.150974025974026,0.322004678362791));
#743=VERTEX_POINT('',#742);
#744=EDGE_CURVE('E617',#743,#713,#736,.T.);
#745=ORIENTED_EDGE('',*,*,#744,.F.);
#746=DIRECTION('',(-1.,0.,0.));
#747=VECTOR('',#746,1.);
#748=CARTESIAN_POINT('',(-6.1,0.150974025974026,0.322004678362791));
#749=LINE('',#748,#747);
#750=EDGE_CURVE('E524',#743,#153,#749,.T.);
#751=ORIENTED_EDGE('',*,*,#750,.T.);
#752=EDGE_LOOP('',(#740,#741,#745,#751));
#753=FACE_BOUND('',#752,.T.);
#754=ADVANCED_FACE('F629',(#753),#739,.F.);
#755=CARTESIAN_POINT('',(-6.1,0.151948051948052,0.322004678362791));
#756=DIRECTION('',(0.,0.,-1.));
#757=DIRECTION('',(-1.,0.,0.));
#758=AXIS2_PLACEMENT_3D('',#755,#756,#757);
#759=PLANE('',#758);
#760=ORIENTED_EDGE('',*,*,#162,.T.);
#761=ORIENTED_EDGE('',*,*,#750,.F.);
#762=DIRECTION('',(0.,-1.,0.));
#763=VECTOR('',#762,1.);
#764=CARTESIAN_POINT('',(-6.1,0.151948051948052,0.322004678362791));
#765=LINE('',#764,#763);
#766=CARTESIAN_POINT('',(-6.1,0.151948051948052,0.322004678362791));
#767=VERTEX_POINT('',#766);
#768=EDGE_CURVE('E623',#767,#743,#765,.T.);
#769=ORIENTED_EDGE('',*,*,#768,.F.);
#770=DIRECTION('',(-1.,0.,0.));
#771=VECTOR('',#770,1.);
#772=CARTESIAN_POINT('',(-6.1,0.151948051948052,0.322004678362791));
#773=LINE('',#772,#771);
#774=EDGE_CURVE('E522',#767,#161,#773,.T.);
#775=ORIENTED_EDGE('',*,*,#774,.T.);
#776=EDGE_LOOP('',(#760,#761,#769,#775));
#777=FACE_BOUND('',#776,.T.);
#778=ADVANCED_FACE('F633',(#777),#759,.F.);
#779=CARTESIAN_POINT('',(-6.1,0.465584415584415,0.675332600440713));
#780=CARTESIAN_POINT('',(-6.1,0.465390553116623,0.661685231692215));
#781=CARTESIAN_POINT('',(-6.1,0.465013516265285,0.635142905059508));
#782=CARTESIAN_POINT('',(-6.1,0.460943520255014,0.596501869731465));
#783=CARTESIAN_POINT('',(-6.1,0.454800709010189,0.560144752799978));
#784=CARTESIAN_POINT('',(-6.1,0.445814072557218,0.526130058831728));
#785=CARTESIAN_POINT('',(-6.1,0.434091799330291,0.494594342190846));
#786=CARTESIAN_POINT('',(-6.1,0.419957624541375,0.465443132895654));
#787=CARTESIAN_POINT('',(-6.1,0.403291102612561,0.43861549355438));
#788=CARTESIAN_POINT('',(-6.1,0.38405660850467,0.414316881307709));
#789=CARTESIAN_POINT('',(-6.1,0.362603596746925,0.392454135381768));
#790=CARTESIAN_POINT('',(-6.1,0.338714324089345,0.373636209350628));
#791=CARTESIAN_POINT('',(-6.1,0.312871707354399,0.35734617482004));
#792=CARTESIAN_POINT('',(-6.1,0.2845745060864,0.344612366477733));
#793=CARTESIAN_POINT('',(-6.1,0.254488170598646,0.334128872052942));
#794=CARTESIAN_POINT('',(-6.1,0.222073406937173,0.327340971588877));
#795=CARTESIAN_POINT('',(-6.1,0.187711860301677,0.322766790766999));
#796=CARTESIAN_POINT('',(-6.1,0.164058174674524,0.322262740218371));
#797=CARTESIAN_POINT('',(-6.1,0.151948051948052,0.322004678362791));
#798=B_SPLINE_CURVE_WITH_KNOTS('',3,(#779,#780,#781,#782,#783,#784,#785,#786,#787,#788,#789,
#790,#791,#792,#793,#794,#795,#796,#797),.UNSPECIFIED.,.F.,.F.,(4,1,1,1,1,1,1,1,1,1,1,1,1,1,1,1,
4),(0.,0.0762312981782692,0.148259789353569,0.216860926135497,0.28210063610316,
0.344528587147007,0.404571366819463,0.462840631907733,0.520642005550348,0.577409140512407,
0.633580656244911,0.690215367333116,0.747647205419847,0.806597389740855,0.867894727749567,
0.932365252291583,1.),.UNSPECIFIED.);
#799=DIRECTION('',(-1.,0.,0.));
#800=VECTOR('',#799,1.);
#801=SURFACE_OF_LINEAR_EXTRUSION('',#798,#800);
#802=ORIENTED_EDGE('',*,*,#186,.T.);
#803=ORIENTED_EDGE('',*,*,#774,.F.);
#804=CARTESIAN_POINT('',(-6.1,0.465584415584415,0.675332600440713));
#805=VERTEX_POINT('',#804);
#806=EDGE_CURVE('E647',#805,#767,#798,.T.);
#807=ORIENTED_EDGE('',*,*,#806,.F.);
#808=DIRECTION('',(-1.,0.,0.));
#809=VECTOR('',#808,1.);
#810=CARTESIAN_POINT('',(-6.1,0.465584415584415,0.675332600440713));
#811=LINE('',#810,#809);
#812=EDGE_CURVE('E520',#805,#185,#811,.T.);
#813=ORIENTED_EDGE('',*,*,#812,.T.);
#814=EDGE_LOOP('',(#802,#803,#807,#813));
#815=FACE_BOUND('',#814,.T.);
#816=ADVANCED_FACE('F639',(#815),#801,.F.);
#817=CARTESIAN_POINT('',(-6.1,0.105438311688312,1.03693974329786));
#818=CARTESIAN_POINT('',(-6.1,0.11934799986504,1.03580067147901));
#819=CARTESIAN_POINT('',(-6.1,0.146499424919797,1.03357722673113));
#820=CARTESIAN_POINT('',(-6.1,0.185775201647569,1.02628780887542));
#821=CARTESIAN_POINT('',(-6.1,0.22277029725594,1.0168665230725));
#822=CARTESIAN_POINT('',(-6.1,0.257477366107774,1.00488137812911));
#823=CARTESIAN_POINT('',(-6.1,0.289494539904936,0.989480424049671));
#824=CARTESIAN_POINT('',(-6.1,0.3194911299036,0.972176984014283));
#825=CARTESIAN_POINT('',(-6.1,0.346539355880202,0.95136528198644));
#826=CARTESIAN_POINT('',(-6.1,0.371544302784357,0.928583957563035));
#827=CARTESIAN_POINT('',(-6.1,0.393568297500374,0.903209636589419));
#828=CARTESIAN_POINT('',(-6.1,0.412996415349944,0.876153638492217));
#829=CARTESIAN_POINT('',(-6.1,0.429163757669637,0.847006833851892));
#830=CARTESIAN_POINT('',(-6.1,0.442575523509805,0.81621233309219));
#831=CARTESIAN_POINT('',(-6.1,0.452754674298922,0.78342871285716));
#832=CARTESIAN_POINT('',(-6.1,0.460379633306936,0.749084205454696));
#833=CARTESIAN_POINT('',(-6.1,0.464776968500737,0.71278460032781));
#834=CARTESIAN_POINT('',(-6.1,0.465311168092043,0.688006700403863));
#835=CARTESIAN_POINT('',(-6.1,0.465584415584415,0.675332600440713));
#836=B_SPLINE_CURVE_WITH_KNOTS('',3,(#817,#818,#819,#820,#821,#822,#823,#824,#825,#826,#827,
#828,#829,#830,#831,#832,#833,#834,#835),.UNSPECIFIED.,.F.,.F.,(4,1,1,1,1,1,1,1,1,1,1,1,1,1,1,1,
4),(0.,0.0733268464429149,0.14313249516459,0.209679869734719,0.273918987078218,0.33576228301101,
0.396210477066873,0.45560885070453,0.514796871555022,0.573764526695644,0.631900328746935,
0.689592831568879,0.748648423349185,0.808163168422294,0.86976604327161,0.933384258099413,1.),.UNSPECIFIED.);
#837=DIRECTION('',(-1.,0.,0.));
#838=VECTOR('',#837,1.);
#839=SURFACE_OF_LINEAR_EXTRUSION('',#836,#838);
#840=ORIENTED_EDGE('',*,*,#210,.T.);
#841=ORIENTED_EDGE('',*,*,#812,.F.);
#842=CARTESIAN_POINT('',(-6.1,0.105438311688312,1.03693974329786));
#843=VERTEX_POINT('',#842);
#844=EDGE_CURVE('E652',#843,#805,#836,.T.);
#845=ORIENTED_EDGE('',*,*,#844,.F.);
#846=DIRECTION('',(-1.,0.,0.));
#847=VECTOR('',#846,1.);
#848=CARTESIAN_POINT('',(-6.1,0.105438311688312,1.03693974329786));
#849=LINE('',#848,#847);
#850=EDGE_CURVE('E518',#843,#209,#849,.T.);
#851=ORIENTED_EDGE('',*,*,#850,.T.);
#852=EDGE_LOOP('',(#840,#841,#845,#851));
#853=FACE_BOUND('',#852,.T.);
#854=ADVANCED_FACE('F643',(#853),#839,.F.);
#855=CARTESIAN_POINT('',(-6.1,0.104707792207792,1.03693974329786));
#856=DIRECTION('',(0.,0.,1.));
#857=DIRECTION('',(1.,0.,0.));
#858=AXIS2_PLACEMENT_3D('',#855,#856,#857);
#859=PLANE('',#858);
#860=ORIENTED_EDGE('',*,*,#218,.T.);
#861=ORIENTED_EDGE('',*,*,#850,.F.);
#862=DIRECTION('',(0.,1.,0.));
#863=VECTOR('',#862,1.);
#864=CARTESIAN_POINT('',(-6.1,0.104707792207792,1.03693974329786));
#865=LINE('',#864,#863);
#866=CARTESIAN_POINT('',(-6.1,0.104707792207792,1.03693974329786));
#867=VERTEX_POINT('',#866);
#868=EDGE_CURVE('E661',#867,#843,#865,.T.);
#869=ORIENTED_EDGE('',*,*,#868,.F.);
#870=DIRECTION('',(-1.,0.,0.));
#871=VECTOR('',#870,1.);
#872=CARTESIAN_POINT('',(-6.1,0.104707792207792,1.03693974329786));
#873=LINE('',#872,#871);
#874=EDGE_CURVE('E516',#867,#217,#873,.T.);
#875=ORIENTED_EDGE('',*,*,#874,.T.);
#876=EDGE_LOOP('',(#860,#861,#869,#875));
#877=FACE_BOUND('',#876,.T.);
#878=ADVANCED_FACE('F738',(#877),#859,.F.);
#879=CARTESIAN_POINT('',(-6.1,0.104707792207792,0.8060955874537));
#880=DIRECTION('',(0.,-1.,0.));
#881=DIRECTION('',(0.,0.,-1.));
#882=AXIS2_PLACEMENT_3D('',#879,#880,#881);
#883=PLANE('',#882);
#884=ORIENTED_EDGE('',*,*,#226,.T.);
#885=ORIENTED_EDGE('',*,*,#874,.F.);
#886=DIRECTION('',(0.,0.,1.));
#887=VECTOR('',#886,1.);
#888=CARTESIAN_POINT('',(-6.1,0.104707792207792,0.8060955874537));
#889=LINE('',#888,#887);
#890=CARTESIAN_POINT('',(-6.1,0.104707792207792,0.8060955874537));
#891=VERTEX_POINT('',#890);
#892=EDGE_CURVE('E667',#891,#867,#889,.T.);
#893=ORIENTED_EDGE('',*,*,#892,.F.);
#894=DIRECTION('',(-1.,0.,0.));
#895=VECTOR('',#894,1.);
#896=CARTESIAN_POINT('',(-6.1,0.104707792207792,0.8060955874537));
#897=LINE('',#896,#895);
#898=EDGE_CURVE('E514',#891,#225,#897,.T.);
#899=ORIENTED_EDGE('',*,*,#898,.T.);
#900=EDGE_LOOP('',(#884,#885,#893,#899));
#901=FACE_BOUND('',#900,.T.);
#902=ADVANCED_FACE('F742',(#901),#883,.F.);
#903=CARTESIAN_POINT('',(-6.1,0.105438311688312,0.8060955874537));
#904=DIRECTION('',(0.,0.,-1.));
#905=DIRECTION('',(-1.,0.,0.));
#906=AXIS2_PLACEMENT_3D('',#903,#904,#905);
#907=PLANE('',#906);
#908=ORIENTED_EDGE('',*,*,#234,.T.);
#909=ORIENTED_EDGE('',*,*,#898,.F.);
#910=DIRECTION('',(0.,-1.,0.));
#911=VECTOR('',#910,1.);
#912=CARTESIAN_POINT('',(-6.1,0.105438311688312,0.8060955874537));
#913=LINE('',#912,#911);
#914=CARTESIAN_POINT('',(-6.1,0.105438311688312,0.8060955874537));
#915=VERTEX_POINT('',#914);
#916=EDGE_CURVE('E670',#915,#891,#913,.T.);
#917=ORIENTED_EDGE('',*,*,#916,.F.);
#918=DIRECTION('',(-1.,0.,0.));
#919=VECTOR('',#918,1.);
#920=CARTESIAN_POINT('',(-6.1,0.105438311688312,0.8060955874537));
#921=LINE('',#920,#919);
#922=EDGE_CURVE('E512',#915,#233,#921,.T.);
#923=ORIENTED_EDGE('',*,*,#922,.T.);
#924=EDGE_LOOP('',(#908,#909,#917,#923));
#925=FACE_BOUND('',#924,.T.);
#926=ADVANCED_FACE('F690',(#925),#907,.F.);
#927=CARTESIAN_POINT('',(-6.1,0.247402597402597,0.673628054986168));
#928=CARTESIAN_POINT('',(-6.1,0.247058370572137,0.682449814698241));
#929=CARTESIAN_POINT('',(-6.1,0.246389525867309,0.699590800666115));
#930=CARTESIAN_POINT('',(-6.1,0.238976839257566,0.723856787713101));
#931=CARTESIAN_POINT('',(-6.1,0.227349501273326,0.745722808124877));
#932=CARTESIAN_POINT('',(-6.1,0.210758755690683,0.764573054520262));
#933=CARTESIAN_POINT('',(-6.1,0.189928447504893,0.78018248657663));
#934=CARTESIAN_POINT('',(-6.1,0.165399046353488,0.792851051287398));
#935=CARTESIAN_POINT('',(-6.1,0.136727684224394,0.801455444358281));
#936=CARTESIAN_POINT('',(-6.1,0.116203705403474,0.804499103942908));
#937=CARTESIAN_POINT('',(-6.1,0.105438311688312,0.8060955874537));
#938=B_SPLINE_CURVE_WITH_KNOTS('',3,(#927,#928,#929,#930,#931,#932,#933,#934,#935,#936,#937),
.UNSPECIFIED.,.F.,.F.,(4,1,1,1,1,1,1,1,4),(0.,0.122603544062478,0.238222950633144,
0.350089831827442,0.465559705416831,0.58502806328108,0.711014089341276,0.848418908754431,1.),.UNSPECIFIED.);
#939=DIRECTION('',(-1.,0.,0.));
#940=VECTOR('',#939,1.);
#941=SURFACE_OF_LINEAR_EXTRUSION('',#938,#940);
#942=ORIENTED_EDGE('',*,*,#250,.T.);
#943=ORIENTED_EDGE('',*,*,#922,.F.);
#944=CARTESIAN_POINT('',(-6.1,0.247402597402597,0.673628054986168));
#945=VERTEX_POINT('',#944);
#946=EDGE_CURVE('E673',#945,#915,#938,.T.);
#947=ORIENTED_EDGE('',*,*,#946,.F.);
#948=DIRECTION('',(-1.,0.,0.));
#949=VECTOR('',#948,1.);
#950=CARTESIAN_POINT('',(-6.1,0.247402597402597,0.673628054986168));
#951=LINE('',#950,#949);
#952=EDGE_CURVE('E510',#945,#249,#951,.T.);
#953=ORIENTED_EDGE('',*,*,#952,.T.);
#954=EDGE_LOOP('',(#942,#943,#947,#953));
#955=FACE_BOUND('',#954,.T.);
#956=ADVANCED_FACE('F686',(#955),#941,.F.);
#957=CARTESIAN_POINT('',(-6.1,0.145616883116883,0.553822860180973));
#958=CARTESIAN_POINT('',(-6.1,0.153289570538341,0.554155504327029));
#959=CARTESIAN_POINT('',(-6.1,0.16798921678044,0.55479279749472));
#960=CARTESIAN_POINT('',(-6.1,0.188701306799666,0.560797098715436));
#961=CARTESIAN_POINT('',(-6.1,0.206738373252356,0.570637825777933));
#962=CARTESIAN_POINT('',(-6.1,0.221636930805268,0.584732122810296));
#963=CARTESIAN_POINT('',(-6.1,0.233420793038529,0.602278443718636));
#964=CARTESIAN_POINT('',(-6.1,0.241725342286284,0.623273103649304));
#965=CARTESIAN_POINT('',(-6.1,0.246487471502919,0.647441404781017));
#966=CARTESIAN_POINT('',(-6.1,0.247086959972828,0.664595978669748));
#967=CARTESIAN_POINT('',(-6.1,0.247402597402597,0.673628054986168));
#968=B_SPLINE_CURVE_WITH_KNOTS('',3,(#957,#958,#959,#960,#961,#962,#963,#964,#965,#966,#967),
.UNSPECIFIED.,.F.,.F.,(4,1,1,1,1,1,1,1,4),(0.,0.128749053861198,0.246662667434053,
0.359069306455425,0.47107757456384,0.588039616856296,0.711712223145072,0.848213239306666,1.),.UNSPECIFIED.);
#969=DIRECTION('',(-1.,0.,0.));
#970=VECTOR('',#969,1.);
#971=SURFACE_OF_LINEAR_EXTRUSION('',#968,#970);
#972=ORIENTED_EDGE('',*,*,#266,.T.);
#973=ORIENTED_EDGE('',*,*,#952,.F.);
#974=CARTESIAN_POINT('',(-6.1,0.145616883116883,0.553822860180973));
#975=VERTEX_POINT('',#974);
#976=EDGE_CURVE('E678',#975,#945,#968,.T.);
#977=ORIENTED_EDGE('',*,*,#976,.F.);
#978=DIRECTION('',(-1.,0.,0.));
#979=VECTOR('',#978,1.);
#980=CARTESIAN_POINT('',(-6.1,0.145616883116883,0.553822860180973));
#981=LINE('',#980,#979);
#982=EDGE_CURVE('E508',#975,#265,#981,.T.);
#983=ORIENTED_EDGE('',*,*,#982,.T.);
#984=EDGE_LOOP('',(#972,#973,#977,#983));
#985=FACE_BOUND('',#984,.T.);
#986=ADVANCED_FACE('F689',(#985),#971,.F.);
#987=CARTESIAN_POINT('',(-6.1,0.143912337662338,0.553822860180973));
#988=DIRECTION('',(0.,0.,1.));
#989=DIRECTION('',(1.,0.,0.));
#990=AXIS2_PLACEMENT_3D('',#987,#988,#989);
#991=PLANE('',#990);
#992=ORIENTED_EDGE('',*,*,#274,.T.);
#993=ORIENTED_EDGE('',*,*,#982,.F.);
#994=DIRECTION('',(0.,1.,0.));
#995=VECTOR('',#994,1.);
#996=CARTESIAN_POINT('',(-6.1,0.143912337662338,0.553822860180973));
#997=LINE('',#996,#995);
#998=CARTESIAN_POINT('',(-6.1,0.143912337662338,0.553822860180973));
#999=VERTEX_POINT('',#998);
#1000=EDGE_CURVE('E348',#999,#975,#997,.T.);
#1001=ORIENTED_EDGE('',*,*,#1000,.F.);
#1002=DIRECTION('',(-1.,0.,0.));
#1003=VECTOR('',#1002,1.);
#1004=CARTESIAN_POINT('',(-6.1,0.143912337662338,0.553822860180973));
#1005=LINE('',#1004,#1003);
#1006=EDGE_CURVE('E506',#999,#273,#1005,.T.);
#1007=ORIENTED_EDGE('',*,*,#1006,.T.);
#1008=EDGE_LOOP('',(#992,#993,#1001,#1007));
#1009=FACE_BOUND('',#1008,.T.);
#1010=ADVANCED_FACE('F359',(#1009),#991,.F.);
#1011=CARTESIAN_POINT('',(-6.1,-0.00267857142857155,0.612020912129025));
#1012=CARTESIAN_POINT('',(-6.1,0.00942362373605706,0.603432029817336));
#1013=CARTESIAN_POINT('',(-6.1,0.0330043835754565,0.586696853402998));
#1014=CARTESIAN_POINT('',(-6.1,0.0653877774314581,0.571550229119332));
#1015=CARTESIAN_POINT('',(-6.1,0.0907767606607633,0.562114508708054));
#1016=CARTESIAN_POINT('',(-6.1,0.109188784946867,0.557617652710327));
#1017=CARTESIAN_POINT('',(-6.1,0.126755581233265,0.554409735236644));
#1018=CARTESIAN_POINT('',(-6.1,0.138298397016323,0.55401489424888));
#1019=CARTESIAN_POINT('',(-6.1,0.143912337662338,0.553822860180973));
#1020=B_SPLINE_CURVE_WITH_KNOTS('',3,(#1011,#1012,#1013,#1014,#1015,#1016,#1017,#1018,#1019),
.UNSPECIFIED.,.F.,.F.,(4,1,1,1,1,1,4),(0.,0.27737542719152,0.540457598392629,0.666416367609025,
0.784009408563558,0.894951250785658,1.),.UNSPECIFIED.);
#1021=DIRECTION('',(-1.,0.,0.));
#1022=VECTOR('',#1021,1.);
#1023=SURFACE_OF_LINEAR_EXTRUSION('',#1020,#1022);
#1024=ORIENTED_EDGE('',*,*,#288,.T.);
#1025=ORIENTED_EDGE('',*,*,#1006,.F.);
#1026=CARTESIAN_POINT('',(-6.1,-0.00267857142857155,0.612020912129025));
#1027=VERTEX_POINT('',#1026);
#1028=EDGE_CURVE('E342',#1027,#999,#1020,.T.);
#1029=ORIENTED_EDGE('',*,*,#1028,.F.);
#1030=DIRECTION('',(-1.,0.,0.));
#1031=VECTOR('',#1030,1.);
#1032=CARTESIAN_POINT('',(-6.1,-0.00267857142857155,0.612020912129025));
#1033=LINE('',#1032,#1031);
#1034=EDGE_CURVE('E504',#1027,#287,#1033,.T.);
#1035=ORIENTED_EDGE('',*,*,#1034,.T.);
#1036=EDGE_LOOP('',(#1024,#1025,#1029,#1035));
#1037=FACE_BOUND('',#1036,.T.);
#1038=ADVANCED_FACE('F354',(#1037),#1023,.F.);
#1039=CARTESIAN_POINT('',(-6.1,-0.545941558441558,1.02208584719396));
#1040=DIRECTION('',(0.,0.602458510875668,0.798150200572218));
#1041=DIRECTION('',(0.,-0.798150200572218,0.602458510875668));
#1042=AXIS2_PLACEMENT_3D('',#1039,#1040,#1041);
#1043=PLANE('',#1042);
#1044=ORIENTED_EDGE('',*,*,#294,.T.);
#1045=ORIENTED_EDGE('',*,*,#1034,.F.);
#1046=DIRECTION('',(0.,0.798150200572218,-0.602458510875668));
#1047=VECTOR('',#1046,1.);
#1048=CARTESIAN_POINT('',(-6.1,-0.545941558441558,1.02208584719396));
#1049=LINE('',#1048,#1047);
#1050=CARTESIAN_POINT('',(-6.1,-0.545941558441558,1.02208584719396));
#1051=VERTEX_POINT('',#1050);
#1052=EDGE_CURVE('E339',#1051,#1027,#1049,.T.);
#1053=ORIENTED_EDGE('',*,*,#1052,.F.);
#1054=DIRECTION('',(-1.,0.,0.));
#1055=VECTOR('',#1054,1.);
#1056=CARTESIAN_POINT('',(-6.1,-0.545941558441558,1.02208584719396));
#1057=LINE('',#1056,#1055);
#1058=EDGE_CURVE('E501',#1051,#105,#1057,.T.);
#1059=ORIENTED_EDGE('',*,*,#1058,.T.);
#1060=EDGE_LOOP('',(#1044,#1045,#1053,#1059));
#1061=FACE_BOUND('',#1060,.T.);
#1062=ADVANCED_FACE('F358',(#1061),#1043,.F.);
#1063=CARTESIAN_POINT('',(-6.1,-0.75,1.02208584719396));
#1064=DIRECTION('',(0.,0.,1.));
#1065=DIRECTION('',(1.,0.,0.));
#1066=AXIS2_PLACEMENT_3D('',#1063,#1064,#1065);
#1067=PLANE('',#1066);
#1068=ORIENTED_EDGE('',*,*,#106,.T.);
#1069=ORIENTED_EDGE('',*,*,#1058,.F.);
#1070=DIRECTION('',(0.,1.,0.));
#1071=VECTOR('',#1070,1.);
#1072=CARTESIAN_POINT('',(-6.1,-0.75,1.02208584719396));
#1073=LINE('',#1072,#1071);
#1074=EDGE_CURVE('E335',#633,#1051,#1073,.T.);
#1075=ORIENTED_EDGE('',*,*,#1074,.F.);
#1076=ORIENTED_EDGE('',*,*,#634,.T.);
#1077=EDGE_LOOP('',(#1068,#1069,#1075,#1076));
#1078=FACE_BOUND('',#1077,.T.);
#1079=ADVANCED_FACE('F364',(#1078),#1067,.F.);
#1080=CARTESIAN_POINT('',(-6.1,0.0663192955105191,0.571638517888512));
#1081=DIRECTION('',(-1.,0.,0.));
#1082=DIRECTION('',(0.,0.,1.));
#1083=AXIS2_PLACEMENT_3D('',#1080,#1081,#1082);
#1084=PLANE('',#1083);
#1085=ORIENTED_EDGE('',*,*,#642,.T.);
#1086=ORIENTED_EDGE('',*,*,#1074,.T.);
#1087=ORIENTED_EDGE('',*,*,#1052,.T.);
#1088=ORIENTED_EDGE('',*,*,#1028,.T.);
#1089=ORIENTED_EDGE('',*,*,#1000,.T.);
#1090=ORIENTED_EDGE('',*,*,#976,.T.);
#1091=ORIENTED_EDGE('',*,*,#946,.T.);
#1092=ORIENTED_EDGE('',*,*,#916,.T.);
#1093=ORIENTED_EDGE('',*,*,#892,.T.);
#1094=ORIENTED_EDGE('',*,*,#868,.T.);
#1095=ORIENTED_EDGE('',*,*,#844,.T.);
#1096=ORIENTED_EDGE('',*,*,#806,.T.);
#1097=ORIENTED_EDGE('',*,*,#768,.T.);
#1098=ORIENTED_EDGE('',*,*,#744,.T.);
#1099=ORIENTED_EDGE('',*,*,#714,.T.);
#1100=ORIENTED_EDGE('',*,*,#690,.T.);
#1101=ORIENTED_EDGE('',*,*,#666,.T.);
#1102=EDGE_LOOP('',(#1085,#1086,#1087,#1088,#1089,#1090,#1091,#1092,#1093,#1094,#1095,#1096,
#1097,#1098,#1099,#1100,#1101));
#1103=FACE_BOUND('',#1102,.T.);
#1104=ADVANCED_FACE('F368',(#1103),#1084,.T.);
#1105=CARTESIAN_POINT('',(-6.1,0.45,-0.311891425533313));
#1106=DIRECTION('',(0.,1.,0.));
#1107=DIRECTION('',(0.,0.,1.));
#1108=AXIS2_PLACEMENT_3D('',#1105,#1106,#1107);
#1109=PLANE('',#1108);
#1110=ORIENTED_EDGE('',*,*,#40,.T.);
#1111=DIRECTION('',(-1.,0.,0.));
#1112=VECTOR('',#1111,1.);
#1113=CARTESIAN_POINT('',(-6.1,0.45,-0.99468363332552));
#1114=LINE('',#1113,#1112);
#1115=CARTESIAN_POINT('',(-6.1,0.45,-0.99468363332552));
#1116=VERTEX_POINT('',#1115);
#1117=EDGE_CURVE('E252',#1116,#29,#1114,.T.);
#1118=ORIENTED_EDGE('',*,*,#1117,.F.);
#1119=DIRECTION('',(0.,0.,-1.));
#1120=VECTOR('',#1119,1.);
#1121=CARTESIAN_POINT('',(-6.1,0.45,-0.311891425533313));
#1122=LINE('',#1121,#1120);
#1123=CARTESIAN_POINT('',(-6.1,0.45,-0.311891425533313));
#1124=VERTEX_POINT('',#1123);
#1125=EDGE_CURVE('E256',#1124,#1116,#1122,.T.);
#1126=ORIENTED_EDGE('',*,*,#1125,.F.);
#1127=DIRECTION('',(-1.,0.,0.));
#1128=VECTOR('',#1127,1.);
#1129=CARTESIAN_POINT('',(-6.1,0.45,-0.311891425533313));
#1130=LINE('',#1129,#1128);
#1131=EDGE_CURVE('E317',#1124,#39,#1130,.T.);
#1132=ORIENTED_EDGE('',*,*,#1131,.T.);
#1133=EDGE_LOOP('',(#1110,#1118,#1126,#1132));
#1134=FACE_BOUND('',#1133,.T.);
#1135=ADVANCED_FACE('F254',(#1134),#1109,.F.);
#1136=CARTESIAN_POINT('',(-6.1,0.0448051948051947,-0.311891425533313));
#1137=DIRECTION('',(0.,0.,1.));
#1138=DIRECTION('',(1.,0.,0.));
#1139=AXIS2_PLACEMENT_3D('',#1136,#1137,#1138);
#1140=PLANE('',#1139);
#1141=ORIENTED_EDGE('',*,*,#48,.T.);
#1142=ORIENTED_EDGE('',*,*,#1131,.F.);
#1143=DIRECTION('',(0.,1.,0.));
#1144=VECTOR('',#1143,1.);
#1145=CARTESIAN_POINT('',(-6.1,0.0448051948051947,-0.311891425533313));
#1146=LINE('',#1145,#1144);
#1147=CARTESIAN_POINT('',(-6.1,0.0448051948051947,-0.311891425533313));
#1148=VERTEX_POINT('',#1147);
#1149=EDGE_CURVE('E262',#1148,#1124,#1146,.T.);
#1150=ORIENTED_EDGE('',*,*,#1149,.F.);
#1151=DIRECTION('',(-1.,0.,0.));
#1152=VECTOR('',#1151,1.);
#1153=CARTESIAN_POINT('',(-6.1,0.0448051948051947,-0.311891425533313));
#1154=LINE('',#1153,#1152);
#1155=EDGE_CURVE('E319',#1148,#47,#1154,.T.);
#1156=ORIENTED_EDGE('',*,*,#1155,.T.);
#1157=EDGE_LOOP('',(#1141,#1142,#1150,#1156));
#1158=FACE_BOUND('',#1157,.T.);
#1159=ADVANCED_FACE('F1000',(#1158),#1140,.F.);
#1160=CARTESIAN_POINT('',(-6.1,0.0448051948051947,-0.537134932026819));
#1161=DIRECTION('',(0.,-1.,0.));
#1162=DIRECTION('',(0.,0.,-1.));
#1163=AXIS2_PLACEMENT_3D('',#1160,#1161,#1162);
#1164=PLANE('',#1163);
#1165=ORIENTED_EDGE('',*,*,#56,.T.);
#1166=ORIENTED_EDGE('',*,*,#1155,.F.);
#1167=DIRECTION('',(0.,0.,1.));
#1168=VECTOR('',#1167,1.);
#1169=CARTESIAN_POINT('',(-6.1,0.0448051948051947,-0.537134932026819));
#1170=LINE('',#1169,#1168);
#1171=CARTESIAN_POINT('',(-6.1,0.0448051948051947,-0.537134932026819));
#1172=VERTEX_POINT('',#1171);
#1173=EDGE_CURVE('E294',#1172,#1148,#1170,.T.);
#1174=ORIENTED_EDGE('',*,*,#1173,.F.);
#1175=DIRECTION('',(-1.,0.,0.));
#1176=VECTOR('',#1175,1.);
#1177=CARTESIAN_POINT('',(-6.1,0.0448051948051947,-0.537134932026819));
#1178=LINE('',#1177,#1176);
#1179=EDGE_CURVE('E321',#1172,#55,#1178,.T.);
#1180=ORIENTED_EDGE('',*,*,#1179,.T.);
#1181=EDGE_LOOP('',(#1165,#1166,#1174,#1180));
#1182=FACE_BOUND('',#1181,.T.);
#1183=ADVANCED_FACE('F1010',(#1182),#1164,.F.);
#1184=CARTESIAN_POINT('',(-6.1,0.231818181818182,-0.537134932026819));
#1185=DIRECTION('',(0.,0.,-1.));
#1186=DIRECTION('',(-1.,0.,0.));
#1187=AXIS2_PLACEMENT_3D('',#1184,#1185,#1186);
#1188=PLANE('',#1187);
#1189=ORIENTED_EDGE('',*,*,#64,.T.);
#1190=ORIENTED_EDGE('',*,*,#1179,.F.);
#1191=DIRECTION('',(0.,-1.,0.));
#1192=VECTOR('',#1191,1.);
#1193=CARTESIAN_POINT('',(-6.1,0.231818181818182,-0.537134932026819));
#1194=LINE('',#1193,#1192);
#1195=CARTESIAN_POINT('',(-6.1,0.231818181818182,-0.537134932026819));
#1196=VERTEX_POINT('',#1195);
#1197=EDGE_CURVE('E291',#1196,#1172,#1194,.T.);
#1198=ORIENTED_EDGE('',*,*,#1197,.F.);
#1199=DIRECTION('',(-1.,0.,0.));
#1200=VECTOR('',#1199,1.);
#1201=CARTESIAN_POINT('',(-6.1,0.231818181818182,-0.537134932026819));
#1202=LINE('',#1201,#1200);
#1203=EDGE_CURVE('E323',#1196,#63,#1202,.T.);
#1204=ORIENTED_EDGE('',*,*,#1203,.T.);
#1205=EDGE_LOOP('',(#1189,#1190,#1198,#1204));
#1206=FACE_BOUND('',#1205,.T.);
#1207=ADVANCED_FACE('F1021',(#1206),#1188,.F.);
#1208=CARTESIAN_POINT('',(-6.1,0.231818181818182,-0.742410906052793));
#1209=DIRECTION('',(0.,-1.,0.));
#1210=DIRECTION('',(0.,0.,-1.));
#1211=AXIS2_PLACEMENT_3D('',#1208,#1209,#1210);
#1212=PLANE('',#1211);
#1213=ORIENTED_EDGE('',*,*,#72,.T.);
#1214=ORIENTED_EDGE('',*,*,#1203,.F.);
#1215=DIRECTION('',(0.,0.,1.));
#1216=VECTOR('',#1215,1.);
#1217=CARTESIAN_POINT('',(-6.1,0.231818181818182,-0.742410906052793));
#1218=LINE('',#1217,#1216);
#1219=CARTESIAN_POINT('',(-6.1,0.231818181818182,-0.742410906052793));
#1220=VERTEX_POINT('',#1219);
#1221=EDGE_CURVE('E288',#1220,#1196,#1218,.T.);
#1222=ORIENTED_EDGE('',*,*,#1221,.F.);
#1223=DIRECTION('',(-1.,0.,0.));
#1224=VECTOR('',#1223,1.);
#1225=CARTESIAN_POINT('',(-6.1,0.231818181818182,-0.742410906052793));
#1226=LINE('',#1225,#1224);
#1227=EDGE_CURVE('E325',#1220,#71,#1226,.T.);
#1228=ORIENTED_EDGE('',*,*,#1227,.T.);
#1229=EDGE_LOOP('',(#1213,#1214,#1222,#1228));
#1230=FACE_BOUND('',#1229,.T.);
#1231=ADVANCED_FACE('F1032',(#1230),#1212,.F.);
#1232=CARTESIAN_POINT('',(-6.1,-0.75,-0.482832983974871));
#1233=DIRECTION('',(0.,0.255602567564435,0.966781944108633));
#1234=DIRECTION('',(0.,-0.966781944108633,0.255602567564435));
#1235=AXIS2_PLACEMENT_3D('',#1232,#1233,#1234);
#1236=PLANE('',#1235);
#1237=ORIENTED_EDGE('',*,*,#80,.T.);
#1238=ORIENTED_EDGE('',*,*,#1227,.F.);
#1239=DIRECTION('',(0.,0.966781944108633,-0.255602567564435));
#1240=VECTOR('',#1239,1.);
#1241=CARTESIAN_POINT('',(-6.1,-0.75,-0.482832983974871));
#1242=LINE('',#1241,#1240);
#1243=CARTESIAN_POINT('',(-6.1,-0.75,-0.482832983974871));
#1244=VERTEX_POINT('',#1243);
#1245=EDGE_CURVE('E285',#1244,#1220,#1242,.T.);
#1246=ORIENTED_EDGE('',*,*,#1245,.F.);
#1247=DIRECTION('',(-1.,0.,0.));
#1248=VECTOR('',#1247,1.);
#1249=CARTESIAN_POINT('',(-6.1,-0.75,-0.482832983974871));
#1250=LINE('',#1249,#1248);
#1251=EDGE_CURVE('E327',#1244,#79,#1250,.T.);
#1252=ORIENTED_EDGE('',*,*,#1251,.T.);
#1253=EDGE_LOOP('',(#1237,#1238,#1246,#1252));
#1254=FACE_BOUND('',#1253,.T.);
#1255=ADVANCED_FACE('F1043',(#1254),#1236,.F.);
#1256=CARTESIAN_POINT('',(-6.1,-0.75,-0.726826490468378));
#1257=DIRECTION('',(0.,-1.,0.));
#1258=DIRECTION('',(0.,0.,-1.));
#1259=AXIS2_PLACEMENT_3D('',#1256,#1257,#1258);
#1260=PLANE('',#1259);
#1261=ORIENTED_EDGE('',*,*,#88,.T.);
#1262=ORIENTED_EDGE('',*,*,#1251,.F.);
#1263=DIRECTION('',(0.,0.,1.));
#1264=VECTOR('',#1263,1.);
#1265=CARTESIAN_POINT('',(-6.1,-0.75,-0.726826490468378));
#1266=LINE('',#1265,#1264);
#1267=CARTESIAN_POINT('',(-6.1,-0.75,-0.726826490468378));
#1268=VERTEX_POINT('',#1267);
#1269=EDGE_CURVE('E282',#1268,#1244,#1266,.T.);
#1270=ORIENTED_EDGE('',*,*,#1269,.F.);
#1271=DIRECTION('',(-1.,0.,0.));
#1272=VECTOR('',#1271,1.);
#1273=CARTESIAN_POINT('',(-6.1,-0.75,-0.726826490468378));
#1274=LINE('',#1273,#1272);
#1275=EDGE_CURVE('E329',#1268,#87,#1274,.T.);
#1276=ORIENTED_EDGE('',*,*,#1275,.T.);
#1277=EDGE_LOOP('',(#1261,#1262,#1270,#1276));
#1278=FACE_BOUND('',#1277,.T.);
#1279=ADVANCED_FACE('F1054',(#1278),#1260,.F.);
#1280=CARTESIAN_POINT('',(-6.1,0.299512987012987,-0.99468363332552));
#1281=DIRECTION('',(0.,-0.247293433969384,-0.968940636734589));
#1282=DIRECTION('',(0.,0.968940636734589,-0.247293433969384));
#1283=AXIS2_PLACEMENT_3D('',#1280,#1281,#1282);
#1284=PLANE('',#1283);
#1285=ORIENTED_EDGE('',*,*,#94,.T.);
#1286=ORIENTED_EDGE('',*,*,#1275,.F.);
#1287=DIRECTION('',(0.,-0.968940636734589,0.247293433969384));
#1288=VECTOR('',#1287,1.);
#1289=CARTESIAN_POINT('',(-6.1,0.299512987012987,-0.99468363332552));
#1290=LINE('',#1289,#1288);
#1291=CARTESIAN_POINT('',(-6.1,0.299512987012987,-0.99468363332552));
#1292=VERTEX_POINT('',#1291);
#1293=EDGE_CURVE('E270',#1292,#1268,#1290,.T.);
#1294=ORIENTED_EDGE('',*,*,#1293,.F.);
#1295=DIRECTION('',(-1.,0.,0.));
#1296=VECTOR('',#1295,1.);
#1297=CARTESIAN_POINT('',(-6.1,0.299512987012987,-0.99468363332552));
#1298=LINE('',#1297,#1296);
#1299=EDGE_CURVE('E261',#1292,#31,#1298,.T.);
#1300=ORIENTED_EDGE('',*,*,#1299,.T.);
#1301=EDGE_LOOP('',(#1285,#1286,#1294,#1300));
#1302=FACE_BOUND('',#1301,.T.);
#1303=ADVANCED_FACE('F1065',(#1302),#1284,.F.);
#1304=CARTESIAN_POINT('',(-6.1,0.45,-0.99468363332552));
#1305=DIRECTION('',(0.,0.,-1.));
#1306=DIRECTION('',(-1.,0.,0.));
#1307=AXIS2_PLACEMENT_3D('',#1304,#1305,#1306);
#1308=PLANE('',#1307);
#1309=ORIENTED_EDGE('',*,*,#32,.T.);
#1310=ORIENTED_EDGE('',*,*,#1299,.F.);
#1311=DIRECTION('',(0.,-1.,0.));
#1312=VECTOR('',#1311,1.);
#1313=CARTESIAN_POINT('',(-6.1,0.45,-0.99468363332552));
#1314=LINE('',#1313,#1312);
#1315=EDGE_CURVE('E265',#1116,#1292,#1314,.T.);
#1316=ORIENTED_EDGE('',*,*,#1315,.F.);
#1317=ORIENTED_EDGE('',*,*,#1117,.T.);
#1318=EDGE_LOOP('',(#1309,#1310,#1316,#1317));
#1319=FACE_BOUND('',#1318,.T.);
#1320=ADVANCED_FACE('F266',(#1319),#1308,.F.);
#1321=CARTESIAN_POINT('',(-6.1,0.,0.));
#1322=DIRECTION('',(-1.,0.,0.));
#1323=DIRECTION('',(0.,0.,1.));
#1324=AXIS2_PLACEMENT_3D('',#1321,#1322,#1323);
#1325=PLANE('',#1324);
#1326=ORIENTED_EDGE('',*,*,#1125,.T.);
#1327=ORIENTED_EDGE('',*,*,#1315,.T.);
#1328=ORIENTED_EDGE('',*,*,#1293,.T.);
#1329=ORIENTED_EDGE('',*,*,#1269,.T.);
#1330=ORIENTED_EDGE('',*,*,#1245,.T.);
#1331=ORIENTED_EDGE('',*,*,#1221,.T.);
#1332=ORIENTED_EDGE('',*,*,#1197,.T.);
#1333=ORIENTED_EDGE('',*,*,#1173,.T.);
#1334=ORIENTED_EDGE('',*,*,#1149,.T.);
#1335=EDGE_LOOP('',(#1326,#1327,#1328,#1329,#1330,#1331,#1332,#1333,#1334));
#1336=FACE_BOUND('',#1335,.T.);
#1337=ADVANCED_FACE('F272',(#1336),#1325,.T.);
#1338=CLOSED_SHELL('',(#368,#388,#408,#425,#457,#481,#505,#529,#553,#577,#594,#609,#621,#652,
#676,#700,#724,#754,#778,#816,#854,#878,#902,#926,#956,#986,#1010,#1038,#1062,#1079,#1104,#1135,
#1159,#1183,#1207,#1231,#1255,#1279,#1303,#1320,#1337));
#1339=MANIFOLD_SOLID_BREP('B2',#1338);
#1340=ADVANCED_BREP_SHAPE_REPRESENTATION('',(#18,#1339),#14);
#1341=SHAPE_DEFINITION_REPRESENTATION(#9,#1340);
ENDSEC;
END-ISO-10303-21;
